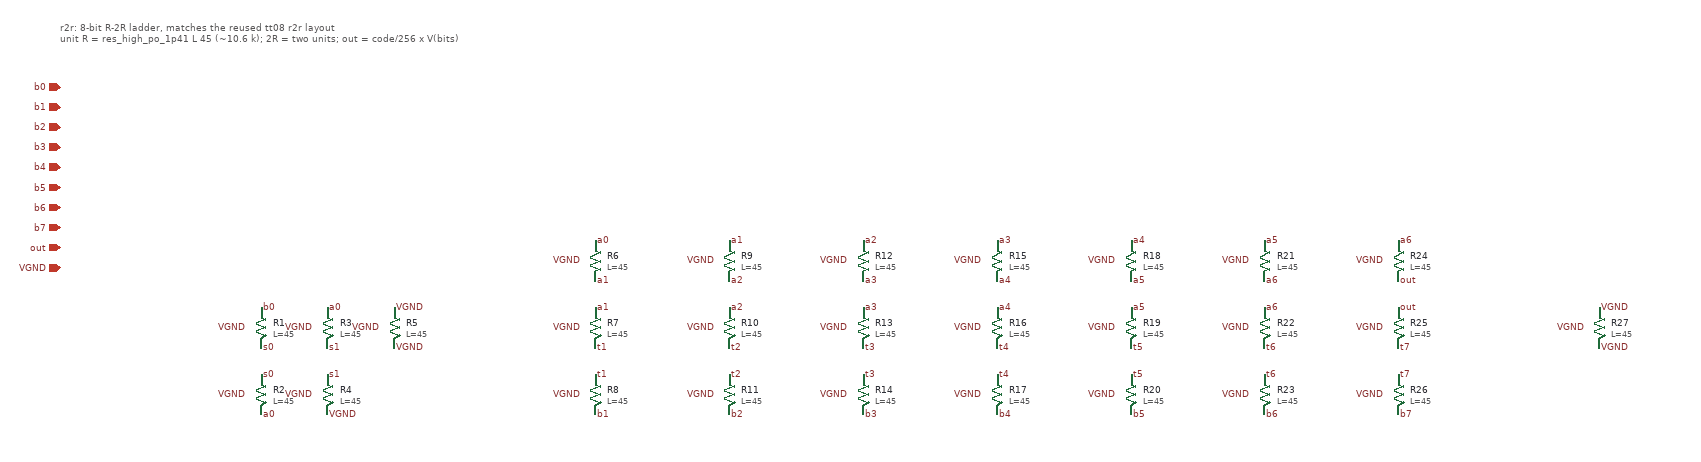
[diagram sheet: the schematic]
v {xschem version=3.4.5 file_version=1.2
}
G {}
K {}
V {}
S {}
E {}
T {r2r: 8-bit R-2R ladder, matches the reused tt08 r2r layout
unit R = res_high_po_1p41 L 45 (~10.6 k); 2R = two units; out = code/256 x V(bits)} -800 -660 0 0 0.4 0.4 {}
C {devices/iopin.sym} -800 -560 0 0 {name=p1
lab=b0}
C {devices/iopin.sym} -800 -530 0 0 {name=p2
lab=b1}
C {devices/iopin.sym} -800 -500 0 0 {name=p3
lab=b2}
C {devices/iopin.sym} -800 -470 0 0 {name=p4
lab=b3}
C {devices/iopin.sym} -800 -440 0 0 {name=p5
lab=b4}
C {devices/iopin.sym} -800 -410 0 0 {name=p6
lab=b5}
C {devices/iopin.sym} -800 -380 0 0 {name=p7
lab=b6}
C {devices/iopin.sym} -800 -350 0 0 {name=p8
lab=b7}
C {devices/iopin.sym} -800 -320 0 0 {name=p9
lab=out}
C {devices/iopin.sym} -800 -290 0 0 {name=p10
lab=VGND}
C {sky130_fd_pr/res_high_po_1p41.sym} -500 -200 0 0 {name=R1
L=45
model=res_high_po_1p41
mult=1
spiceprefix=X}
C {devices/lab_pin.sym} -500 -230 0 1 {name=p11
sig_type=std_logic
lab=b0}
C {devices/lab_pin.sym} -500 -170 0 1 {name=p12
sig_type=std_logic
lab=s0}
C {devices/lab_pin.sym} -520 -200 0 0 {name=p13
sig_type=std_logic
lab=VGND}
C {sky130_fd_pr/res_high_po_1p41.sym} -500 -100 0 0 {name=R2
L=45
model=res_high_po_1p41
mult=1
spiceprefix=X}
C {devices/lab_pin.sym} -500 -130 0 1 {name=p14
sig_type=std_logic
lab=s0}
C {devices/lab_pin.sym} -500 -70 0 1 {name=p15
sig_type=std_logic
lab=a0}
C {devices/lab_pin.sym} -520 -100 0 0 {name=p16
sig_type=std_logic
lab=VGND}
C {sky130_fd_pr/res_high_po_1p41.sym} -400 -200 0 0 {name=R3
L=45
model=res_high_po_1p41
mult=1
spiceprefix=X}
C {devices/lab_pin.sym} -400 -230 0 1 {name=p17
sig_type=std_logic
lab=a0}
C {devices/lab_pin.sym} -400 -170 0 1 {name=p18
sig_type=std_logic
lab=s1}
C {devices/lab_pin.sym} -420 -200 0 0 {name=p19
sig_type=std_logic
lab=VGND}
C {sky130_fd_pr/res_high_po_1p41.sym} -400 -100 0 0 {name=R4
L=45
model=res_high_po_1p41
mult=1
spiceprefix=X}
C {devices/lab_pin.sym} -400 -130 0 1 {name=p20
sig_type=std_logic
lab=s1}
C {devices/lab_pin.sym} -400 -70 0 1 {name=p21
sig_type=std_logic
lab=VGND}
C {devices/lab_pin.sym} -420 -100 0 0 {name=p22
sig_type=std_logic
lab=VGND}
C {sky130_fd_pr/res_high_po_1p41.sym} -300 -200 0 0 {name=R5
L=45
model=res_high_po_1p41
mult=1
spiceprefix=X}
C {devices/lab_pin.sym} -300 -230 0 1 {name=p23
sig_type=std_logic
lab=VGND}
C {devices/lab_pin.sym} -300 -170 0 1 {name=p24
sig_type=std_logic
lab=VGND}
C {devices/lab_pin.sym} -320 -200 0 0 {name=p25
sig_type=std_logic
lab=VGND}
C {sky130_fd_pr/res_high_po_1p41.sym} 0 -300 0 0 {name=R6
L=45
model=res_high_po_1p41
mult=1
spiceprefix=X}
C {devices/lab_pin.sym} 0 -330 0 1 {name=p26
sig_type=std_logic
lab=a0}
C {devices/lab_pin.sym} 0 -270 0 1 {name=p27
sig_type=std_logic
lab=a1}
C {devices/lab_pin.sym} -20 -300 0 0 {name=p28
sig_type=std_logic
lab=VGND}
C {sky130_fd_pr/res_high_po_1p41.sym} 0 -200 0 0 {name=R7
L=45
model=res_high_po_1p41
mult=1
spiceprefix=X}
C {devices/lab_pin.sym} 0 -230 0 1 {name=p29
sig_type=std_logic
lab=a1}
C {devices/lab_pin.sym} 0 -170 0 1 {name=p30
sig_type=std_logic
lab=t1}
C {devices/lab_pin.sym} -20 -200 0 0 {name=p31
sig_type=std_logic
lab=VGND}
C {sky130_fd_pr/res_high_po_1p41.sym} 0 -100 0 0 {name=R8
L=45
model=res_high_po_1p41
mult=1
spiceprefix=X}
C {devices/lab_pin.sym} 0 -130 0 1 {name=p32
sig_type=std_logic
lab=t1}
C {devices/lab_pin.sym} 0 -70 0 1 {name=p33
sig_type=std_logic
lab=b1}
C {devices/lab_pin.sym} -20 -100 0 0 {name=p34
sig_type=std_logic
lab=VGND}
C {sky130_fd_pr/res_high_po_1p41.sym} 200 -300 0 0 {name=R9
L=45
model=res_high_po_1p41
mult=1
spiceprefix=X}
C {devices/lab_pin.sym} 200 -330 0 1 {name=p35
sig_type=std_logic
lab=a1}
C {devices/lab_pin.sym} 200 -270 0 1 {name=p36
sig_type=std_logic
lab=a2}
C {devices/lab_pin.sym} 180 -300 0 0 {name=p37
sig_type=std_logic
lab=VGND}
C {sky130_fd_pr/res_high_po_1p41.sym} 200 -200 0 0 {name=R10
L=45
model=res_high_po_1p41
mult=1
spiceprefix=X}
C {devices/lab_pin.sym} 200 -230 0 1 {name=p38
sig_type=std_logic
lab=a2}
C {devices/lab_pin.sym} 200 -170 0 1 {name=p39
sig_type=std_logic
lab=t2}
C {devices/lab_pin.sym} 180 -200 0 0 {name=p40
sig_type=std_logic
lab=VGND}
C {sky130_fd_pr/res_high_po_1p41.sym} 200 -100 0 0 {name=R11
L=45
model=res_high_po_1p41
mult=1
spiceprefix=X}
C {devices/lab_pin.sym} 200 -130 0 1 {name=p41
sig_type=std_logic
lab=t2}
C {devices/lab_pin.sym} 200 -70 0 1 {name=p42
sig_type=std_logic
lab=b2}
C {devices/lab_pin.sym} 180 -100 0 0 {name=p43
sig_type=std_logic
lab=VGND}
C {sky130_fd_pr/res_high_po_1p41.sym} 400 -300 0 0 {name=R12
L=45
model=res_high_po_1p41
mult=1
spiceprefix=X}
C {devices/lab_pin.sym} 400 -330 0 1 {name=p44
sig_type=std_logic
lab=a2}
C {devices/lab_pin.sym} 400 -270 0 1 {name=p45
sig_type=std_logic
lab=a3}
C {devices/lab_pin.sym} 380 -300 0 0 {name=p46
sig_type=std_logic
lab=VGND}
C {sky130_fd_pr/res_high_po_1p41.sym} 400 -200 0 0 {name=R13
L=45
model=res_high_po_1p41
mult=1
spiceprefix=X}
C {devices/lab_pin.sym} 400 -230 0 1 {name=p47
sig_type=std_logic
lab=a3}
C {devices/lab_pin.sym} 400 -170 0 1 {name=p48
sig_type=std_logic
lab=t3}
C {devices/lab_pin.sym} 380 -200 0 0 {name=p49
sig_type=std_logic
lab=VGND}
C {sky130_fd_pr/res_high_po_1p41.sym} 400 -100 0 0 {name=R14
L=45
model=res_high_po_1p41
mult=1
spiceprefix=X}
C {devices/lab_pin.sym} 400 -130 0 1 {name=p50
sig_type=std_logic
lab=t3}
C {devices/lab_pin.sym} 400 -70 0 1 {name=p51
sig_type=std_logic
lab=b3}
C {devices/lab_pin.sym} 380 -100 0 0 {name=p52
sig_type=std_logic
lab=VGND}
C {sky130_fd_pr/res_high_po_1p41.sym} 600 -300 0 0 {name=R15
L=45
model=res_high_po_1p41
mult=1
spiceprefix=X}
C {devices/lab_pin.sym} 600 -330 0 1 {name=p53
sig_type=std_logic
lab=a3}
C {devices/lab_pin.sym} 600 -270 0 1 {name=p54
sig_type=std_logic
lab=a4}
C {devices/lab_pin.sym} 580 -300 0 0 {name=p55
sig_type=std_logic
lab=VGND}
C {sky130_fd_pr/res_high_po_1p41.sym} 600 -200 0 0 {name=R16
L=45
model=res_high_po_1p41
mult=1
spiceprefix=X}
C {devices/lab_pin.sym} 600 -230 0 1 {name=p56
sig_type=std_logic
lab=a4}
C {devices/lab_pin.sym} 600 -170 0 1 {name=p57
sig_type=std_logic
lab=t4}
C {devices/lab_pin.sym} 580 -200 0 0 {name=p58
sig_type=std_logic
lab=VGND}
C {sky130_fd_pr/res_high_po_1p41.sym} 600 -100 0 0 {name=R17
L=45
model=res_high_po_1p41
mult=1
spiceprefix=X}
C {devices/lab_pin.sym} 600 -130 0 1 {name=p59
sig_type=std_logic
lab=t4}
C {devices/lab_pin.sym} 600 -70 0 1 {name=p60
sig_type=std_logic
lab=b4}
C {devices/lab_pin.sym} 580 -100 0 0 {name=p61
sig_type=std_logic
lab=VGND}
C {sky130_fd_pr/res_high_po_1p41.sym} 800 -300 0 0 {name=R18
L=45
model=res_high_po_1p41
mult=1
spiceprefix=X}
C {devices/lab_pin.sym} 800 -330 0 1 {name=p62
sig_type=std_logic
lab=a4}
C {devices/lab_pin.sym} 800 -270 0 1 {name=p63
sig_type=std_logic
lab=a5}
C {devices/lab_pin.sym} 780 -300 0 0 {name=p64
sig_type=std_logic
lab=VGND}
C {sky130_fd_pr/res_high_po_1p41.sym} 800 -200 0 0 {name=R19
L=45
model=res_high_po_1p41
mult=1
spiceprefix=X}
C {devices/lab_pin.sym} 800 -230 0 1 {name=p65
sig_type=std_logic
lab=a5}
C {devices/lab_pin.sym} 800 -170 0 1 {name=p66
sig_type=std_logic
lab=t5}
C {devices/lab_pin.sym} 780 -200 0 0 {name=p67
sig_type=std_logic
lab=VGND}
C {sky130_fd_pr/res_high_po_1p41.sym} 800 -100 0 0 {name=R20
L=45
model=res_high_po_1p41
mult=1
spiceprefix=X}
C {devices/lab_pin.sym} 800 -130 0 1 {name=p68
sig_type=std_logic
lab=t5}
C {devices/lab_pin.sym} 800 -70 0 1 {name=p69
sig_type=std_logic
lab=b5}
C {devices/lab_pin.sym} 780 -100 0 0 {name=p70
sig_type=std_logic
lab=VGND}
C {sky130_fd_pr/res_high_po_1p41.sym} 1000 -300 0 0 {name=R21
L=45
model=res_high_po_1p41
mult=1
spiceprefix=X}
C {devices/lab_pin.sym} 1000 -330 0 1 {name=p71
sig_type=std_logic
lab=a5}
C {devices/lab_pin.sym} 1000 -270 0 1 {name=p72
sig_type=std_logic
lab=a6}
C {devices/lab_pin.sym} 980 -300 0 0 {name=p73
sig_type=std_logic
lab=VGND}
C {sky130_fd_pr/res_high_po_1p41.sym} 1000 -200 0 0 {name=R22
L=45
model=res_high_po_1p41
mult=1
spiceprefix=X}
C {devices/lab_pin.sym} 1000 -230 0 1 {name=p74
sig_type=std_logic
lab=a6}
C {devices/lab_pin.sym} 1000 -170 0 1 {name=p75
sig_type=std_logic
lab=t6}
C {devices/lab_pin.sym} 980 -200 0 0 {name=p76
sig_type=std_logic
lab=VGND}
C {sky130_fd_pr/res_high_po_1p41.sym} 1000 -100 0 0 {name=R23
L=45
model=res_high_po_1p41
mult=1
spiceprefix=X}
C {devices/lab_pin.sym} 1000 -130 0 1 {name=p77
sig_type=std_logic
lab=t6}
C {devices/lab_pin.sym} 1000 -70 0 1 {name=p78
sig_type=std_logic
lab=b6}
C {devices/lab_pin.sym} 980 -100 0 0 {name=p79
sig_type=std_logic
lab=VGND}
C {sky130_fd_pr/res_high_po_1p41.sym} 1200 -300 0 0 {name=R24
L=45
model=res_high_po_1p41
mult=1
spiceprefix=X}
C {devices/lab_pin.sym} 1200 -330 0 1 {name=p80
sig_type=std_logic
lab=a6}
C {devices/lab_pin.sym} 1200 -270 0 1 {name=p81
sig_type=std_logic
lab=out}
C {devices/lab_pin.sym} 1180 -300 0 0 {name=p82
sig_type=std_logic
lab=VGND}
C {sky130_fd_pr/res_high_po_1p41.sym} 1200 -200 0 0 {name=R25
L=45
model=res_high_po_1p41
mult=1
spiceprefix=X}
C {devices/lab_pin.sym} 1200 -230 0 1 {name=p83
sig_type=std_logic
lab=out}
C {devices/lab_pin.sym} 1200 -170 0 1 {name=p84
sig_type=std_logic
lab=t7}
C {devices/lab_pin.sym} 1180 -200 0 0 {name=p85
sig_type=std_logic
lab=VGND}
C {sky130_fd_pr/res_high_po_1p41.sym} 1200 -100 0 0 {name=R26
L=45
model=res_high_po_1p41
mult=1
spiceprefix=X}
C {devices/lab_pin.sym} 1200 -130 0 1 {name=p86
sig_type=std_logic
lab=t7}
C {devices/lab_pin.sym} 1200 -70 0 1 {name=p87
sig_type=std_logic
lab=b7}
C {devices/lab_pin.sym} 1180 -100 0 0 {name=p88
sig_type=std_logic
lab=VGND}
C {sky130_fd_pr/res_high_po_1p41.sym} 1500 -200 0 0 {name=R27
L=45
model=res_high_po_1p41
mult=1
spiceprefix=X}
C {devices/lab_pin.sym} 1500 -230 0 1 {name=p89
sig_type=std_logic
lab=VGND}
C {devices/lab_pin.sym} 1500 -170 0 1 {name=p90
sig_type=std_logic
lab=VGND}
C {devices/lab_pin.sym} 1480 -200 0 0 {name=p91
sig_type=std_logic
lab=VGND}
